# LEF
# LEF file generated by Abstract Generator version 5.5.10 on Jul 31 16:51:52 2004
#
# Contains LEF for all bins.
# Options:   [x] Antenna
#            [x] Geometry
#            [x] Technology

VERSION 5.7 ;
BUSBITCHARS "[]" ;
DIVIDERCHAR "/" ;
UNITS
  DATABASE MICRONS 1000 ;
END UNITS

USEMINSPACING OBS ON ;
CLEARANCEMEASURE EUCLIDEAN ;

# MANUFACTURINGGRID 0.15 ;

# LAYER nwell
#   TYPE	MASTERSLICE ;
# END nwell
# 
# LAYER nactive
#   TYPE	MASTERSLICE ;
# END nactive
# 
# LAYER pactive
#   TYPE	MASTERSLICE ;
# END pactive

# LAYER poly
#   TYPE	MASTERSLICE ;
# END poly
# 
# LAYER cc
#   TYPE	CUT ;
#   SPACING	0.9 ;
# END cc

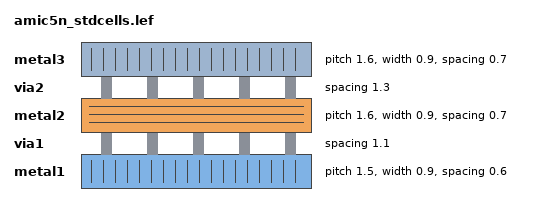
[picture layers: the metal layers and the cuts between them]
LAYER metal1
  TYPE		ROUTING ;
  DIRECTION	VERTICAL ;
  PITCH		1.5  ;
  OFFSET	1.5 ;
  WIDTH		0.9 ;
  SPACING	0.6 ;
  RESISTANCE	RPERSQ 0.085 ;
  CAPACITANCE	CPERSQDIST 3.2e-05 ;
END metal1

LAYER via1
  TYPE	CUT ;
  SPACING	1.1
    CENTERTOCENTER ;
#  PROPERTY contactResistance 1.0 ;
END via1

LAYER metal2
  TYPE		ROUTING ;
  DIRECTION	HORIZONTAL ;
  PITCH		1.6 ;
  OFFSET	0.0 ;
  WIDTH		0.9 ;
  SPACING	0.7 ;
  RESISTANCE	RPERSQ 0.085 ;
  CAPACITANCE	CPERSQDIST 1.6e-05 ;
END metal2

LAYER via2
  TYPE	CUT ;
  SPACING	1.3 
    CENTERTOCENTER ;
#  PROPERTY contactResistance 1.0 ;
END via2

LAYER metal3
  TYPE		ROUTING ;
  DIRECTION	VERTICAL ;
  PITCH		1.6 ;
  OFFSET	1.5 ;
  WIDTH		0.9 ;
  SPACING	0.7 ;
  RESISTANCE	RPERSQ 0.040 ;
  CAPACITANCE	CPERSQDIST 1e-05 ;
END metal3

# SPACING
#   SAMENET cc  via	0.150 ;
#   SAMENET via  via2	0.150 ;
# END SPACING

VIA M2_M1 DEFAULT
  LAYER metal1 ;
    RECT -0.450 -0.450 0.450 0.450 ;
  LAYER via1 ;
    RECT -0.250 -0.250 0.250 0.250 ;
  LAYER metal2 ;
    RECT -0.450 -0.450 0.450 0.450 ;
END M2_M1

VIA M3_M2 DEFAULT
  LAYER metal2 ;
    RECT -0.450 -0.450 0.450 0.450 ;
  LAYER via2 ;
    RECT -0.250 -0.250 0.250 0.250 ;
  LAYER metal3 ;
    RECT -0.450 -0.450 0.450 0.450 ;
END M3_M2

VIARULE viagen21 GENERATE
  LAYER metal1 ;
    ENCLOSURE 0.2 0.2 ;
  LAYER metal2 ;
    ENCLOSURE 0.2 0.2 ;
  LAYER via1 ;
    RECT -0.25 -0.25 0.25 0.25 ;
    SPACING 1.1 BY 1.1 ;
END viagen21

VIARULE viagen32 GENERATE
  LAYER metal3 ;
    ENCLOSURE 0.2 0.2 ;
  LAYER metal2 ;
    ENCLOSURE 0.2 0.2 ;
  LAYER via2 ;
    RECT -0.25 -0.25 0.25 0.25 ;
    SPACING 1.3 BY 1.3 ;
END viagen32

# VIARULE viagen21 GENERATE
#   LAYER metal1 ;
#     WIDTH 1.2 TO 120 ;
#     DIRECTION VERTICAL ;
#     OVERHANG 0.2 ;
#   LAYER metal2 ;
#     WIDTH 1.2 TO 120 ;
#     DIRECTION HORIZONTAL ;
#     OVERHANG 0.2 ;
#   LAYER via1 ;
#     RECT -0.25 -0.25 0.25 0.25 ;
#     SPACING 1.1 BY 1.1 ;
# END viagen21
# 
# VIARULE viagen32 GENERATE
#   LAYER metal3 ;
#     WIDTH 1.8 TO 180 ;
#     DIRECTION VERTICAL ;
#     OVERHANG 0.2 ;
#   LAYER metal2 ;
#     WIDTH 1.2 TO 120 ;
#     DIRECTION HORIZONTAL ;
#     OVERHANG 0.2 ;
#   LAYER via2 ;
#     RECT -0.25 -0.25 0.25 0.25 ;
#     SPACING 1.3 BY 1.3 ;
# END viagen32

# VIARULE TURN1 GENERATE
#   LAYER metal1 ;
#     DIRECTION VERTICAL ;
#   LAYER metal1 ;
#     DIRECTION HORIZONTAL ;
# END TURN1
# 
# VIARULE TURN2 GENERATE
#   LAYER metal2 ;
#     DIRECTION HORIZONTAL ;
#   LAYER metal2 ;
#     DIRECTION VERTICAL ;
# END TURN2
# 
# VIARULE TURN3 GENERATE
#   LAYER metal3 ;
#     DIRECTION VERTICAL ;
#   LAYER metal3 ;
#     DIRECTION HORIZONTAL ;
# END TURN3

SITE  core
    CLASS	CORE ;
    SYMMETRY	Y ;
    SIZE	1.500 BY 14.400 ;
END  core

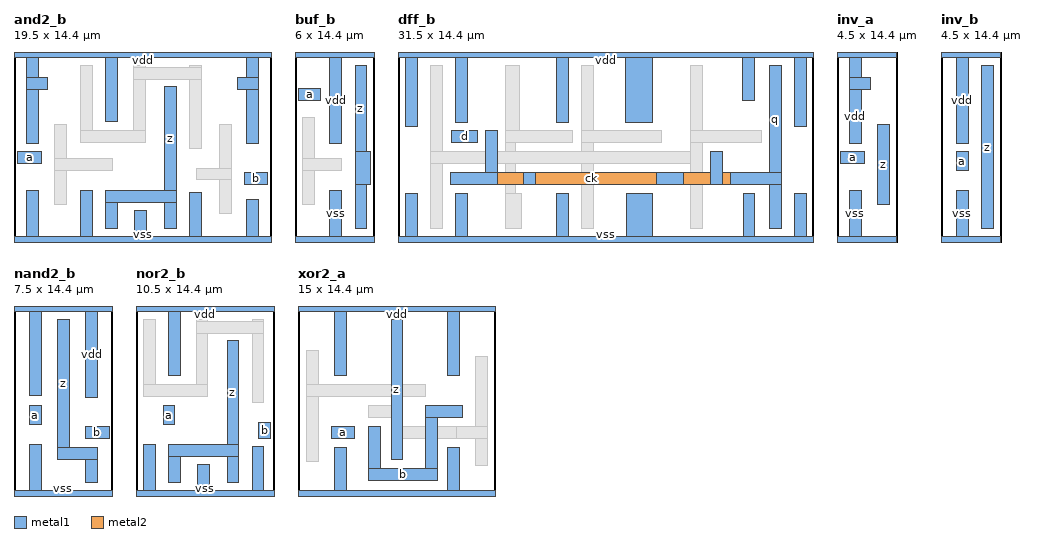
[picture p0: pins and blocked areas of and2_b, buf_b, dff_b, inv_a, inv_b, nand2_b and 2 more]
MACRO and2_b
  CLASS CORE ;
  FOREIGN and2_b 0.000 0.000 ;
  ORIGIN 0.000 0.000 ;
  SIZE 19.500 BY 14.400 ;
  SYMMETRY X Y ;
  SITE core ;
  PIN z
    DIRECTION OUTPUT ;
    PORT
      LAYER metal1 ;
        RECT 11.400 3.900 12.300 11.750 ;
        RECT 6.950 3.000 12.300 3.900 ;
        RECT 6.950 1.050 7.850 3.000 ;
        RECT 11.400 1.050 12.300 3.000 ;
    END
  END z
  PIN a
    DIRECTION INPUT ;
    ANTENNAGATEAREA 1.860000 ;
    PORT
      LAYER metal1 ;
        RECT 0.300 5.950 2.050 6.850 ;
    END
  END a
  PIN b
    DIRECTION INPUT ;
    ANTENNAGATEAREA 1.860000 ;
    PORT
      LAYER metal1 ;
        RECT 17.450 4.350 19.200 5.250 ;
    END
  END b
  PIN vdd
    DIRECTION INOUT ;
    USE POWER ;
    SHAPE ABUTMENT ;
    PORT
      LAYER metal1 ;
        RECT 0.000 13.950 19.500 14.400 ;
        RECT 0.950 12.450 1.850 13.950 ;
        RECT 0.950 11.550 2.550 12.450 ;
        RECT 0.950 7.450 1.850 11.550 ;
        RECT 6.950 9.150 7.850 13.950 ;
        RECT 17.650 12.450 18.550 13.950 ;
        RECT 16.950 11.550 18.550 12.450 ;
        RECT 17.650 7.450 18.550 11.550 ;
    END
  END vdd
  PIN vss
    DIRECTION INOUT ;
    USE GROUND ;
    SHAPE ABUTMENT ;
    PORT
      LAYER metal1 ;
        RECT 0.950 0.450 1.850 3.900 ;
        RECT 5.050 0.450 5.950 3.900 ;
        RECT 9.150 0.450 10.050 2.400 ;
        RECT 13.300 0.450 14.200 3.750 ;
        RECT 17.650 0.450 18.550 3.200 ;
        RECT 0.000 0.000 19.500 0.450 ;
    END
  END vss
  OBS
      LAYER metal1 ;
        RECT 3.050 6.300 3.950 8.900 ;
        RECT 5.050 8.450 5.950 13.350 ;
        RECT 9.050 13.250 9.950 13.350 ;
        RECT 13.300 13.250 14.200 13.350 ;
        RECT 9.050 12.350 14.200 13.250 ;
        RECT 9.050 8.450 9.950 12.350 ;
        RECT 5.050 7.550 9.950 8.450 ;
        RECT 13.300 7.100 14.200 12.350 ;
        RECT 3.050 5.400 7.450 6.300 ;
        RECT 15.550 5.600 16.450 8.900 ;
        RECT 3.050 2.850 3.950 5.400 ;
        RECT 13.800 4.700 16.450 5.600 ;
        RECT 15.550 2.150 16.450 4.700 ;
  END
END and2_b

MACRO buf_b
  CLASS CORE ;
  FOREIGN buf_b 0.000 0.000 ;
  ORIGIN 0.000 0.000 ;
  SIZE 6.000 BY 14.400 ;
  SYMMETRY X Y ;
  SITE core ;
  PIN z
    DIRECTION OUTPUT ;
    PORT
      LAYER metal1 ;
        RECT 4.550 6.850 5.450 13.350 ;
        RECT 4.550 4.350 5.700 6.850 ;
        RECT 4.550 1.050 5.450 4.350 ;
    END
  END z
  PIN a
    DIRECTION INPUT ;
    ANTENNAGATEAREA 1.860000 ;
    PORT
      LAYER metal1 ;
        RECT 0.300 10.750 1.950 11.650 ;
    END
  END a
  PIN vdd
    DIRECTION INOUT ;
    USE POWER ;
    SHAPE ABUTMENT ;
    PORT
      LAYER metal1 ;
        RECT 0.000 13.950 6.000 14.400 ;
        RECT 2.650 7.450 3.550 13.950 ;
    END
  END vdd
  PIN vss
    DIRECTION INOUT ;
    USE GROUND ;
    SHAPE ABUTMENT ;
    PORT
      LAYER metal1 ;
        RECT 2.650 0.450 3.550 3.900 ;
        RECT 0.000 0.000 6.000 0.450 ;
    END
  END vss
  OBS
      LAYER metal1 ;
        RECT 0.550 6.300 1.450 9.450 ;
        RECT 0.550 5.400 3.550 6.300 ;
        RECT 0.550 2.850 1.450 5.400 ;
  END
END buf_b

MACRO dff_b
  CLASS CORE ;
  FOREIGN dff_b 0.000 0.000 ;
  ORIGIN 0.000 0.000 ;
  SIZE 31.500 BY 14.400 ;
  SYMMETRY X Y ;
  SITE core ;
  PIN q
    DIRECTION OUTPUT ;
    ANTENNAGATEAREA 3.360000 ;
    PORT
      LAYER metal1 ;
        RECT 28.150 5.250 29.050 13.350 ;
        RECT 25.200 4.350 29.050 5.250 ;
        RECT 28.150 1.050 29.050 4.350 ;
    END
  END q
  PIN d
    DIRECTION INPUT ;
    ANTENNAGATEAREA 4.560000 ;
    PORT
      LAYER metal1 ;
        RECT 4.050 7.550 6.050 8.450 ;
    END
  END d
  PIN ck
    DIRECTION INPUT ;
    ANTENNAGATEAREA 17.039999 ;
    PORT
      LAYER metal1 ;
        RECT 6.650 5.250 7.550 8.450 ;
        RECT 3.950 4.350 7.550 5.250 ;
        RECT 9.500 4.350 10.400 5.250 ;
        RECT 19.600 4.350 21.600 5.250 ;
        RECT 23.700 4.350 24.600 6.850 ;
      LAYER metal2 ;
        RECT 3.950 4.350 25.450 5.250 ;
    END
  END ck
  PIN vdd
    DIRECTION INOUT ;
    USE POWER ;
    SHAPE ABUTMENT ;
    PORT
      LAYER metal1 ;
        RECT 0.000 13.950 31.500 14.400 ;
        RECT 0.550 8.750 1.450 13.950 ;
        RECT 4.350 9.050 5.250 13.950 ;
        RECT 12.000 9.050 12.900 13.950 ;
        RECT 17.250 9.050 19.300 13.950 ;
        RECT 26.100 10.750 27.000 13.950 ;
        RECT 30.050 8.750 30.950 13.950 ;
    END
  END vdd
  PIN vss
    DIRECTION INOUT ;
    USE GROUND ;
    SHAPE ABUTMENT ;
    PORT
      LAYER metal1 ;
        RECT 0.550 0.450 1.450 3.650 ;
        RECT 4.350 0.450 5.250 3.650 ;
        RECT 12.000 0.450 12.900 3.650 ;
        RECT 17.300 0.450 19.300 3.650 ;
        RECT 26.150 0.450 27.050 3.650 ;
        RECT 30.050 0.450 30.950 3.650 ;
        RECT 0.000 0.000 31.500 0.450 ;
    END
  END vss
  OBS
      LAYER metal1 ;
        RECT 2.450 6.850 3.350 13.350 ;
        RECT 8.150 8.450 9.200 13.350 ;
        RECT 13.900 8.450 14.800 13.350 ;
        RECT 22.200 8.450 23.100 13.350 ;
        RECT 8.150 7.550 13.250 8.450 ;
        RECT 13.900 7.550 19.950 8.450 ;
        RECT 22.200 7.550 27.550 8.450 ;
        RECT 2.450 5.950 4.450 6.850 ;
        RECT 2.450 1.050 3.350 5.950 ;
        RECT 8.150 3.650 8.900 7.550 ;
        RECT 9.500 5.950 11.500 6.850 ;
        RECT 13.900 5.250 14.800 7.550 ;
        RECT 19.600 5.950 21.600 6.850 ;
        RECT 11.000 4.350 14.800 5.250 ;
        RECT 8.150 1.050 9.350 3.650 ;
        RECT 13.900 1.050 14.800 4.350 ;
        RECT 22.200 1.050 23.100 7.550 ;
      LAYER metal2 ;
        RECT 2.450 5.950 22.200 6.850 ;
  END
END dff_b

MACRO inv_a
  CLASS CORE ;
  FOREIGN inv_a 0.000 0.000 ;
  ORIGIN 0.000 0.000 ;
  SIZE 4.500 BY 14.400 ;
  SYMMETRY X Y ;
  SITE core ;
  PIN z
    DIRECTION OUTPUT ;
    PORT
      LAYER metal1 ;
        RECT 3.050 2.850 3.950 8.900 ;
    END
  END z
  PIN a
    DIRECTION INPUT ;
    ANTENNAGATEAREA 1.860000 ;
    PORT
      LAYER metal1 ;
        RECT 0.300 5.950 2.050 6.850 ;
    END
  END a
  PIN vdd
    DIRECTION INOUT ;
    USE POWER ;
    SHAPE ABUTMENT ;
    PORT
      LAYER metal1 ;
        RECT 0.000 13.950 4.500 14.400 ;
        RECT 0.950 12.450 1.850 13.950 ;
        RECT 0.950 11.550 2.550 12.450 ;
        RECT 0.950 7.450 1.850 11.550 ;
    END
  END vdd
  PIN vss
    DIRECTION INOUT ;
    USE GROUND ;
    SHAPE ABUTMENT ;
    PORT
      LAYER metal1 ;
        RECT 0.950 0.450 1.850 3.900 ;
        RECT 0.000 0.000 4.500 0.450 ;
    END
  END vss
END inv_a

MACRO inv_b
  CLASS CORE ;
  FOREIGN inv_b 0.000 0.000 ;
  ORIGIN 0.000 0.000 ;
  SIZE 4.500 BY 14.400 ;
  SYMMETRY X Y ;
  SITE core ;
  PIN z
    DIRECTION OUTPUT ;
    PORT
      LAYER metal1 ;
        RECT 3.050 1.050 3.950 13.350 ;
    END
  END z
  PIN a
    DIRECTION INPUT ;
    ANTENNAGATEAREA 5.700000 ;
    PORT
      LAYER metal1 ;
        RECT 1.150 5.400 2.050 6.850 ;
    END
  END a
  PIN vdd
    DIRECTION INOUT ;
    USE POWER ;
    SHAPE ABUTMENT ;
    PORT
      LAYER metal1 ;
        RECT 0.000 13.950 4.500 14.400 ;
        RECT 1.150 7.450 2.050 13.950 ;
    END
  END vdd
  PIN vss
    DIRECTION INOUT ;
    USE GROUND ;
    SHAPE ABUTMENT ;
    PORT
      LAYER metal1 ;
        RECT 1.150 0.450 2.050 3.900 ;
        RECT 0.000 0.000 4.500 0.450 ;
    END
  END vss
END inv_b

MACRO nand2_b
  CLASS CORE ;
  FOREIGN nand2_b 0.000 0.000 ;
  ORIGIN 0.000 0.000 ;
  SIZE 7.500 BY 14.400 ;
  SYMMETRY X Y ;
  SITE core ;
  PIN z
    DIRECTION OUTPUT ;
    PORT
      LAYER metal1 ;
        RECT 3.300 3.650 4.200 13.350 ;
        RECT 3.300 2.750 6.350 3.650 ;
        RECT 5.450 1.050 6.350 2.750 ;
    END
  END z
  PIN a
    DIRECTION INPUT ;
    ANTENNAGATEAREA 5.700000 ;
    PORT
      LAYER metal1 ;
        RECT 1.150 5.400 2.050 6.850 ;
    END
  END a
  PIN b
    DIRECTION INPUT ;
    ANTENNAGATEAREA 5.700000 ;
    PORT
      LAYER metal1 ;
        RECT 5.450 4.350 7.200 5.250 ;
    END
  END b
  PIN vdd
    DIRECTION INOUT ;
    USE POWER ;
    SHAPE ABUTMENT ;
    PORT
      LAYER metal1 ;
        RECT 0.000 13.950 7.500 14.400 ;
        RECT 1.150 7.600 2.050 13.950 ;
        RECT 5.450 7.450 6.350 13.950 ;
    END
  END vdd
  PIN vss
    DIRECTION INOUT ;
    USE GROUND ;
    SHAPE ABUTMENT ;
    PORT
      LAYER metal1 ;
        RECT 1.150 0.450 2.050 3.900 ;
        RECT 0.000 0.000 7.500 0.450 ;
    END
  END vss
END nand2_b

MACRO nor2_b
  CLASS CORE ;
  FOREIGN nor2_b 0.000 0.000 ;
  ORIGIN 0.000 0.000 ;
  SIZE 10.500 BY 14.400 ;
  SYMMETRY X Y ;
  SITE core ;
  PIN z
    DIRECTION OUTPUT ;
    PORT
      LAYER metal1 ;
        RECT 6.900 3.900 7.800 11.750 ;
        RECT 2.450 3.000 7.800 3.900 ;
        RECT 2.450 1.050 3.350 3.000 ;
        RECT 6.900 1.050 7.800 3.000 ;
    END
  END z
  PIN a
    DIRECTION INPUT ;
    ANTENNAGATEAREA 9.570000 ;
    PORT
      LAYER metal1 ;
        RECT 2.050 5.400 2.950 6.850 ;
    END
  END a
  PIN b
    DIRECTION INPUT ;
    ANTENNAGATEAREA 9.570000 ;
    PORT
      LAYER metal1 ;
        RECT 9.300 4.350 10.200 5.600 ;
    END
  END b
  PIN vdd
    DIRECTION INOUT ;
    USE POWER ;
    SHAPE ABUTMENT ;
    PORT
      LAYER metal1 ;
        RECT 0.000 13.950 10.500 14.400 ;
        RECT 2.450 9.150 3.350 13.950 ;
    END
  END vdd
  PIN vss
    DIRECTION INOUT ;
    USE GROUND ;
    SHAPE ABUTMENT ;
    PORT
      LAYER metal1 ;
        RECT 0.550 0.450 1.450 3.900 ;
        RECT 4.650 0.450 5.550 2.400 ;
        RECT 8.800 0.450 9.700 3.750 ;
        RECT 0.000 0.000 10.500 0.450 ;
    END
  END vss
  OBS
      LAYER metal1 ;
        RECT 0.550 8.450 1.450 13.350 ;
        RECT 4.550 13.250 5.450 13.350 ;
        RECT 8.800 13.250 9.700 13.350 ;
        RECT 4.550 12.350 9.700 13.250 ;
        RECT 4.550 8.450 5.450 12.350 ;
        RECT 0.550 7.550 5.450 8.450 ;
        RECT 8.800 7.100 9.700 12.350 ;
  END
END nor2_b

MACRO xor2_a
  CLASS CORE ;
  FOREIGN xor2_a 0.000 0.000 ;
  ORIGIN 0.000 0.000 ;
  SIZE 15.000 BY 14.400 ;
  SYMMETRY X Y ;
  SITE core ;
  PIN z
    DIRECTION OUTPUT ;
    PORT
      LAYER metal1 ;
        RECT 7.050 2.750 7.950 13.350 ;
    END
  END z
  PIN a
    DIRECTION INPUT ;
    ANTENNAGATEAREA 6.570000 ;
    PORT
      LAYER metal1 ;
        RECT 2.550 4.350 4.300 5.250 ;
    END
  END a
  PIN b
    DIRECTION INPUT ;
    ANTENNAGATEAREA 6.570000 ;
    PORT
      LAYER metal1 ;
        RECT 9.650 5.950 12.450 6.850 ;
        RECT 5.350 2.050 6.250 5.250 ;
        RECT 9.650 2.050 10.550 5.950 ;
        RECT 5.350 1.150 10.550 2.050 ;
    END
  END b
  PIN vdd
    DIRECTION INOUT ;
    USE POWER ;
    SHAPE ABUTMENT ;
    PORT
      LAYER metal1 ;
        RECT 0.000 13.950 15.000 14.400 ;
        RECT 2.750 9.150 3.650 13.950 ;
        RECT 11.350 9.150 12.250 13.950 ;
    END
  END vdd
  PIN vss
    DIRECTION INOUT ;
    USE GROUND ;
    SHAPE ABUTMENT ;
    PORT
      LAYER metal1 ;
        RECT 2.750 0.450 3.650 3.650 ;
        RECT 11.350 0.450 12.250 3.650 ;
        RECT 0.000 0.000 15.000 0.450 ;
    END
  END vss
  OBS
      LAYER metal1 ;
        RECT 0.650 2.600 1.550 11.000 ;
        RECT 8.750 7.550 9.650 8.450 ;
        RECT 5.350 5.950 6.250 6.850 ;
        RECT 13.450 5.250 14.350 10.600 ;
        RECT 11.150 4.350 14.350 5.250 ;
        RECT 13.450 2.300 14.350 4.350 ;
      LAYER metal2 ;
        RECT 0.650 7.550 9.650 8.450 ;
        RECT 5.350 5.950 7.950 6.850 ;
        RECT 7.050 5.250 7.950 5.950 ;
        RECT 7.050 4.350 12.050 5.250 ;
  END
END xor2_a

END LIBRARY
